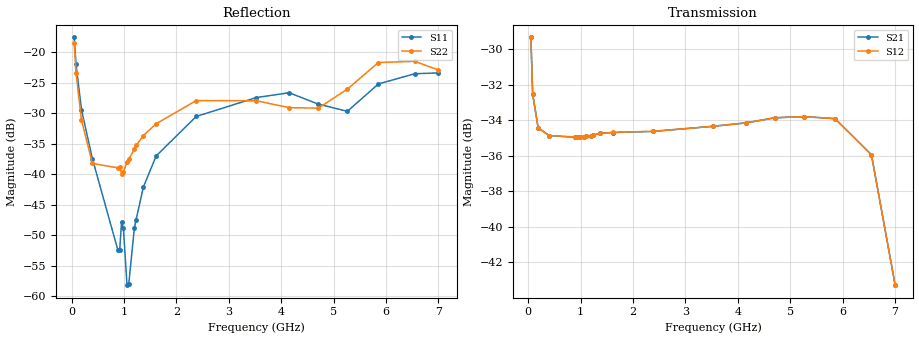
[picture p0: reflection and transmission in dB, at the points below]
! Integrated Device Technology
! Corporate Headquarters
! 6024 Silver Creek Valley Road
! San Jose, CA 95138  USA
! Phone:  1-408-284-8200
! Toll Free:  1-800-223-1366
! Webpage:  http://www.idt.com/
! Timing and RF Division
! 515 Groton Road, Suite 102
! Westford, MA 01886-6024
! Device:  F2258
! Description: Voltage Variable RF Attenuator
! Frequency:  50.0 -  6000.00 MHz
! Package:  3x3 mm Thin QFN Plastic Package: 16 pin
! Ports:  2 RF, 2 DC
!  Pin  1  = NC
!  Pin  2  = NC
!  Pin  3  = RF2  = Port 2
!  Pin  4  = GND
!  Pin  5  = Vdd
!  Pin  6  = NC
!  Pin  7  = VCTRL
!  Pin  8  = NC
!  Pin  9  = GND
!  Pin 10  = RF1  = Port 1
!  Pin 11  = NC
!  Pin 12  = NC
!  Pin 13  = NC
!  Pin 14  = NC
!  Pin 15  = NC
!  Pin 16  = NC
! Vcntrl:  1.990 Volts
! Vdd:  +3.300 Volts
! Current:  1.156 mA
! Data:  The device was measured on a the F2258 evaluation board which has
!  individual transmission lines to the RF pins.  Data was collected
!  using a calibrated network analyzer.  The evaluation board was
!  de-embedded using a TRL calibration technique.
!  The reference plane is the edge of the package pin.
! Misc:  SN 10
!  Action Tracker AT0285
! Date Measured:  2014-12-10
! Date:  2016-01-13  MJV
! Note:
!  Integrated Device Technology supplies this data as a sample of measured
!  data at the package pin for this product.  Your particular data for this
!  product may vary.
!  Data was taken at 25 degrees C.
!  Integrated Device Technology reserves the right to change this data at anytime.
!Freq_(GHz)  S11M_(dB)  S11P_(deg)  S21M_(dB)  S21P_(deg)  S12M_(dB)  S12P_(deg)  S22M_(dB)  S22P_(deg)
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# GHz S dB R 50
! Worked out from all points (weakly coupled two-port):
!   201 points, 50 MHz to 7 GHz, reference 50 ohm
!   highest |S21| = -29.33 dB at 50 MHz (marker M1); lowest = -43.3 dB at 7 GHz (marker M2)
!   lowest |S11| = -58.2 dB at 1.058 GHz (marker M3), VSWR 1.00, Z = 49.9 + j0.0554 ohm
!   |S11| at or under -10 dB: start of sweep to end of sweep
!   |S22| runs from -39.9 to -18.5 dB; largest |S21 - S12| = 8.6e-05
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0.05  -17.55 -110.9  -29.33 -66.5  -29.33 -66.5  -18.54 -107.8
0.08475  -21.97 -107.3  -32.54 -47.0  -32.53 -47.0  -23.40 -98.3
0.189  -29.41 -109.3  -34.43 -23.9  -34.43 -23.9  -31.11 -82.6
0.3975  -37.47 -118.9  -34.86 -13.0  -34.86 -13.0  -38.22 -44.9
0.884  -52.47 166.6  -34.96 -8.7  -34.94 -8.7  -38.95 14.9
0.91875  -52.35 149.7  -34.95 -8.6  -34.94 -8.6  -38.86 16.4
0.9535  -47.77 -162.3  -34.96 -8.5  -34.95 -8.5  -39.90 33.7
0.98825  -48.86 -173.4  -34.94 -8.4  -34.93 -8.4  -39.67 30.6
1.05775  -58.18 153.2  -34.92 -8.3  -34.92 -8.3  -37.95 29.0
1.0925  -57.92 116.3  -34.91 -8.3  -34.90 -8.3  -37.54 28.8
1.19675  -48.83 55.7  -34.87 -8.5  -34.87 -8.5  -35.89 27.0
1.2315  -47.43 45.5  -34.84 -8.4  -34.84 -8.4  -35.28 25.5
1.3705  -42.07 36.5  -34.74 -8.9  -34.74 -8.9  -33.65 24.6
1.61375  -36.99 32.4  -34.69 -10.3  -34.68 -10.2  -31.71 21.8
2.37825  -30.52 48.0  -34.63 -14.1  -34.62 -14.1  -27.92 23.4
3.525  -27.42 91.5  -34.34 -20.9  -34.34 -20.9  -27.94 50.4
4.1505  -26.63 104.9  -34.15 -25.5  -34.15 -25.5  -29.07 60.2
4.7065  -28.49 95.6  -33.86 -30.2  -33.86 -30.2  -29.16 41.6
5.2625  -29.67 54.2  -33.79 -36.3  -33.80 -36.3  -26.03 6.1
5.85325  -25.19 29.8  -33.91 -46.7  -33.91 -46.7  -21.67 -11.6
6.54825  -23.51 45.0  -35.94 -66.8  -35.95 -66.8  -21.48 -45.0
7  -23.38 84.4  -43.27 -62.6  -43.29 -62.2  -22.90 -127.7
